VERSION 5.8 ;
DIVIDERCHAR "/" ;
BUSBITCHARS "[]" ;
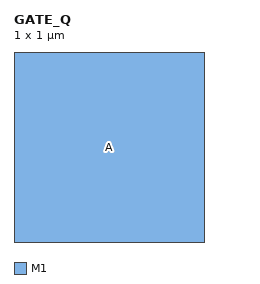
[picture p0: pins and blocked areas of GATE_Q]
MACRO GATE_Q
  CLASS CORE ;
  ORIGIN 0 0 ;
  SIZE 1 BY 1 ;
  SITE CORE ;
  PIN A
    DIRECTION INPUT ;
    USE SIGNAL ;
    ANTENNAGATEAREA 1 LAYER M1 ;
    ANTENNAGATEAREA 4 LAYER M2 ;
    ANTENNADIFFAREA 3 LAYER M2 ;
    PORT
      LAYER M1 ;
        RECT 0 0 1 1 ;
    END
  END A
END GATE_Q
END LIBRARY
